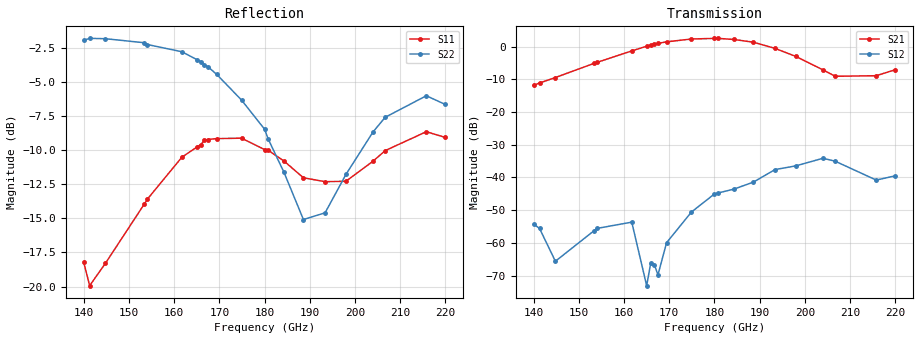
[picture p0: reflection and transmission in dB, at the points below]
!  2-Port S-parameters saved by WinCal
! VAR MeasName=S-Parameters (CALIBRATED_DATA) read from VNA (ZVA67-4Port)
! VAR MeasDate=6/13/2018 12:01:58 PM
! VAR NAME=tx_220GHz_Vadj_refl_1V1
! VAR FILENAME=tx_220GHz_Vadj_refl_1V1.S2P
! VAR DATE=6/13/2018 12:01:58 PM
! VAR PHYS_PORTS=1,2
# Hz S MA R 50
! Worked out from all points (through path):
!   801 points, 140 GHz to 220 GHz, reference 50 ohm
!   highest |S21| = 2.49 dB at 180.8 GHz (marker M1); lowest = -11.8 dB at 140 GHz (marker M2)
!   group delay of S21, straight-line fit = 25.6 ps
!   lowest |S11| = -19.9 dB at 141.3 GHz (marker M3), VSWR 1.22, Z = 49.8 - j10.1 ohm
!   |S11| at or under -10 dB: start of sweep to 164 GHz; 164.3144 GHz to 164.4836 GHz (169.2 MHz wide, 0.103 % of centre); 180.8 GHz to 207.1 GHz (26.28 GHz wide, 13.6 % of centre)
!   |S22| runs from -16.6 to -1.7 dB; largest |S21 - S12| = 1.3
!   S11 on the Smith chart (normalised r, x): 140 GHz: 1.10, -0.24; 154.1 GHz: 0.68, +0.15; 169.4 GHz: 0.94, +0.72; 188.6 GHz: 1.56, -0.33; 204 GHz: 0.59, -0.21; 220 GHz: 0.60, +0.42
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1.4e11  0.1225 -60.5  0.256 136.3  0.001943 -32.4  0.7988 34.5
1.413e11  0.1007 -85.6  0.2773 128.7  0.001665 -51.0  0.8119 32.4
1.448e11  0.1217 -125.5  0.3362 103.8  0.0005258 -128.7  0.8095 27.0
1.534e11  0.2006 155.3  0.5543 35.4  0.001547 102.7  0.7824 12.0
1.541e11  0.2093 150.6  0.5754 29.5  0.001673 83.8  0.7706 10.9
1.617e11  0.2977 112.4  0.8568 -37.9  0.00208 -53.6  0.7253 -3.7
1.65e11  0.3241 95.6  1.011 -70.8  0.0002227 28.1  0.6789 -11.8
1.659e11  0.3313 91.1  1.051 -80.5  0.000494 78.9  0.6666 -14.8
1.667e11  0.3432 86.0  1.088 -88.9  0.0004627 31.4  0.6493 -16.7
1.675e11  0.3458 82.7  1.118 -97.5  0.0003264 -136.3  0.6382 -19.7
1.694e11  0.3484 74.3  1.179 -117.3  0.001009 7.2  0.5995 -23.3
1.749e11  0.3497 48.3  1.302 -176.3  0.002967 -40.1  0.4825 -37.8
1.8e11  0.3178 24.5  1.331 130.0  0.005608 -86.5  0.3772 -53.5
1.808e11  0.3157 21.9  1.332 121.0  0.005802 -88.4  0.3473 -56.6
1.843e11  0.2883 2.1  1.281 83.0  0.006646 -114.8  0.2621 -80.6
1.886e11  0.2504 -23.1  1.164 37.3  0.008492 -119.9  0.176 -126.6
1.934e11  0.2422 -59.8  0.936 -13.7  0.01321 -142.9  0.1863 160.1
1.98e11  0.2431 -98.5  0.7057 -57.9  0.01504 -166.2  0.2574 117.4
2.04e11  0.2879 -145.3  0.4406 -103.5  0.01965 158.1  0.3685 88.7
2.067e11  0.3149 -166.0  0.3511 -117.5  0.01773 136.7  0.4172 78.6
2.158e11  0.3693 140.7  0.3583 -147.8  0.009128 126.5  0.5002 39.6
2.2e11  0.3519 118.5  0.4423 -176.9  0.01061 143.6  0.4647 19.3
